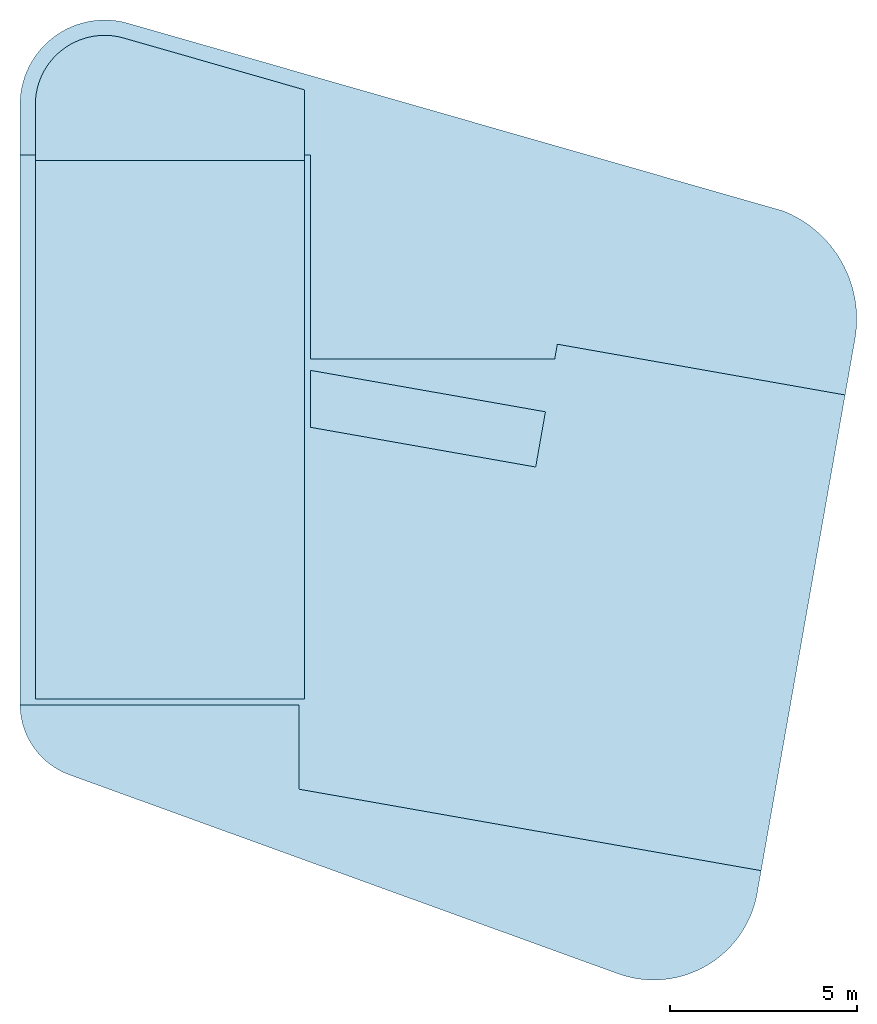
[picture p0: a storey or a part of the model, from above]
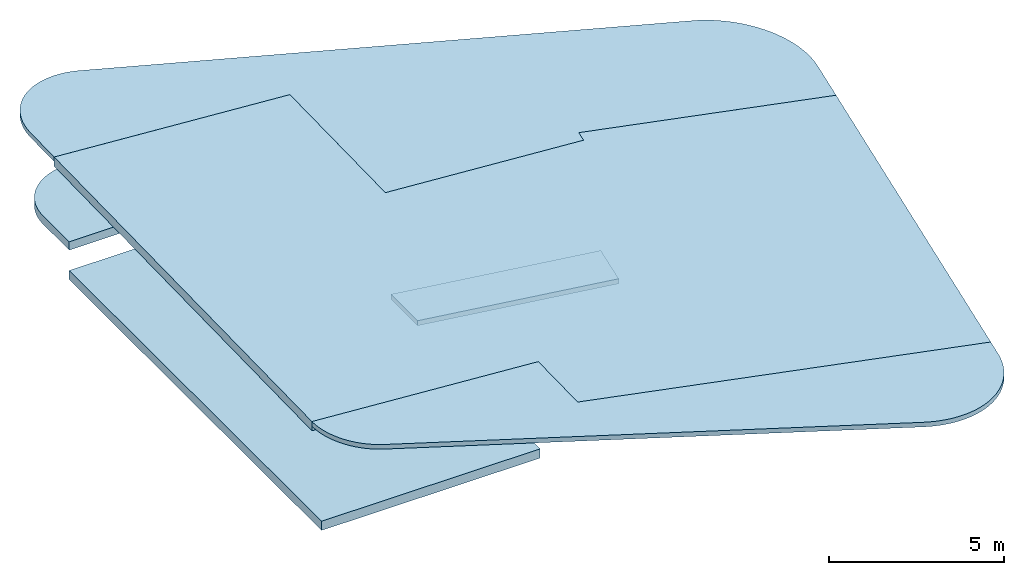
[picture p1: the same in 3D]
Properties of the parts of a building model (IFC2X3)

# File
Description: ViewDefinition [CoordinationView_V2.0, QuantityTakeOffAddOnView]
Time: 2021-04-29T08:18:13
Author: IMd, imd@imdbv.nl
Organization: IMd Raadgevende Ingenieurs
Written by: The EXPRESS Data Manager Version 5.02.0100.07 : 28 Aug 2013
Made in: 20200826_1250(x64) - Exporter 20.2.1.0 - Alternate UI 20.2.1.0
Comment: STEP Physical File produced by: The EXPRESS Data Manager Version 5.02.0100.07 : 28 Aug 2013 * Module: EDMstepFileFactory/EDMstandAlone * Creation date: Thu Apr 29 08:18:13 2021 * Host: mod-prod-vdi-07 * Database: C:\Users\sl\AppData\Local\Temp\82545038-9e77-4e2a-bcb9-289da51b45b7\7ef8d0ce-2a1d-49f6-8344-e9309f1aad8b\ifc * Database version: 5507 * Database creation date: Thu Apr 29 08:18:07 2021 * Schema: IFC2X3 * Model: DataRepository.ifc * Model creation date: Thu Apr 29 08:18:07 2021 * Header model: DataRepository.ifc_HeaderModel * Header model creation date: Thu Apr 29 08:18:07 2021 * EDMuser: sdai-user * EDMgroup: sdai-group * License ID and type: 5605 : Permanent license. Expiry date: * EDMstepFileFactory options: 020000

# IfcProject
Phase: DO

# IfcSite, Default
RefLatitude: 52, 13, 20, 148010; RefLongitude: 5, 11, 12, 352981; RefElevation: 0 mm
Pset_ProductRequirements - Category: Project Information

# IfcBuilding, IFc
LongName: IFc
Pset_BuildingCommon - NumberOfStoreys: 4
Pset_ProductRequirements - Category: Project Information

# IfcBuildingStorey: Level:IMd_hulplevel (3)
In: IFc
Pset_ProductRequirements - Category: Levels
Name | LongName = Pset_AirSideSystemInformation, Name = Pset_ProductRequirements, Name | Elevation (mm)
00 begane grond b.k. ruwe vloer | 00 begane grond b.k. ruwe vloer | -70
01 1e verd. b.k. ruwe vloer | 01 1e verd. b.k. ruwe vloer | 3000
02 2e verd. b.k. ruwe vloer | 02 2e verd. b.k. ruwe vloer | 3700

# IfcBuildingStorey: Level:IMd_niveau naam en peil, -01 kelder
In: IFc
LongName: -01 kelder; Elevation: -4000 mm
Pset_AirSideSystemInformation - Name: Inheiniveau NAP -11,5m
Pset_ProductRequirements - Name: Inheiniveau NAP -11,5m; Category: Levels

# IfcBeam: NLRS_28_SF_LIB_balk buis_generiek_ISR:ø139.7x8 (3)
In: 00 begane grond b.k. ruwe vloer
Type - Pset_BeamCommon - IsExternal: no; LoadBearing: yes; Reference: NLRS_28_SF_LIB_balk buis_generiek_ISR:ø139.7x8
Type - Pset_ProductRequirements - Category: Structural Framing
Type - Pset_QuantityTakeOff - Reference: NLRS_28_SF_LIB_balk buis_generiek_ISR:ø139.7x8
Type - Pset_ReinforcementBarPitchOfBeam - Description: ø139.7x8; Reference: NLRS_28_SF_LIB_balk buis_generiek_ISR:ø139.7x8
Type - S_IMd_IFC_(28)_SF_Stalen liggers - Assembly Code: 28.11; Assembly Description: hoofddraagconstructies; kolommen en liggers, kolom-/liggerconstructies
Classification: 28.11 hoofddraagconstructies; kolommen en liggers, kolom-/liggerconstructies (NL-SfB nummercode); Material: IMd_staal
BaseQuantities - CrossSectionArea: 0.00330954 m2
S_IMd_IFC_(28)_SF_Stalen liggers - Start Extension: 0 mm; Cross-Section Rotation: 0 deg; Family: NLRS_28_SF_LIB_balk buis_generiek_ISR: ø139.7x8; Type: NLRS_28_SF_LIB_balk buis_generiek_ISR: ø139.7x8; Reference Level: Level: 00 begane grond b.k. ruwe vloer; Reference Level Elevation: -70 mm; z Offset Value: 0 mm
Name (NLRS_28_SF_LIB_balk buis_generiek_ISR:ø139.7x8:...) | BaseQuantities, Length (mm) = Cut Length (mm) | OuterSurfaceArea (m2) | GrossVolume (m3) | NetVolume (m3) | Span (mm) = S_IMd_IFC_(28)_SF_Stalen liggers, Length (mm) | Slope (deg) | Start Level Offset (mm) | End Level Offset (mm) | End Extension (mm) | GrossSurfaceArea (m2) | NetSurfaceArea (m2)
1046224 | 5552.17 | 4594393 | 18.3751 | 0.0183834 | 5389.27 | 73.6005 | 678.499 | 5848.51 | 162.901 | 2436738 | 4.60102 | S_IMd_IFC_(28)_SF_Stalen liggers - Comments: (3x)
1046332 | 5520 | 4567775 | 18.2687 | 0.0182769 | 5520 | 78.9309 | 676.053 | 6093.36 | 0 | 2422620 | 4.5744
1046638 | 5481.06 | 4535556 | 18.1398 | 0.0181479 | 5260 | 79 | 702.677 | 5866.04 | 221.064 | 2405532 | 4.54218

# IfcBeam: NLRS_28_SF_LIB_balk hout gelamineerd_generiek_ISR:HB 140x350 (2)
In: 00 begane grond b.k. ruwe vloer
Type - Pset_BeamCommon - IsExternal: no; LoadBearing: yes; Reference: NLRS_28_SF_LIB_balk hout gelamineerd_generiek_ISR:HB 140x350
Type - Pset_ProductRequirements - Category: Structural Framing
Type - Pset_QuantityTakeOff - Reference: NLRS_28_SF_LIB_balk hout gelamineerd_generiek_ISR:HB 140x350
Type - Pset_ReinforcementBarPitchOfBeam - Description: gelamineerde ligger 180x550; Reference: NLRS_28_SF_LIB_balk hout gelamineerd_generiek_ISR:HB 140x350
Type - S_IMd_IFC_(28)_SF_Stalen liggers - Assembly Code: 28.11; Assembly Description: hoofddraagconstructies; kolommen en liggers, kolom-/liggerconstructies
Classification: 28.11 hoofddraagconstructies; kolommen en liggers, kolom-/liggerconstructies (NL-SfB nummercode); Material: IMd_hout
BaseQuantities - GrossSurfaceArea: 0 m2; NetVolume: 0.618238 m3; Length: 12606 mm; NetSurfaceArea: 12.4628 m2
Pset_BeamCommon - Slope: 0 deg; Span: 12606 mm
S_IMd_IFC_(28)_SF_Stalen liggers - Start Level Offset: 0 mm; End Level Offset: 0 mm; Start Extension: 0 mm; End Extension: 0 mm; Cross-Section Rotation: 0 deg; Structural Material: IMd_hout; Family: NLRS_28_SF_LIB_balk hout gelamineerd_generiek_ISR: HB 140x350; Type: NLRS_28_SF_LIB_balk hout gelamineerd_generiek_ISR: HB 140x350; Reference Level: Level: 01 eerste verdieping; Reference Level Elevation: 3000 mm; Elevation at Top: 2982 mm; Elevation at Bottom: 2632 mm; z Offset Value: -18 mm; Length: 12606 mm; Cut Length: 12617.1 mm; Comments: (GL)
Name (NLRS_28_SF_LIB_balk hout gelamineerd_generiek_ISR:HB 140x350:...)
998395
998734

# IfcBeam: NLRS_28_SF_LIB_balk hout gelamineerd_generiek_ISR:HB 180x550 (4)
In: 00 begane grond b.k. ruwe vloer
Type - Pset_BeamCommon - IsExternal: no; LoadBearing: yes; Reference: NLRS_28_SF_LIB_balk hout gelamineerd_generiek_ISR:HB 180x550
Type - Pset_ProductRequirements - Category: Structural Framing
Type - Pset_QuantityTakeOff - Reference: NLRS_28_SF_LIB_balk hout gelamineerd_generiek_ISR:HB 180x550
Type - Pset_ReinforcementBarPitchOfBeam - Description: gelamineerde ligger 180x550; Reference: NLRS_28_SF_LIB_balk hout gelamineerd_generiek_ISR:HB 180x550
Type - S_IMd_IFC_(28)_SF_Stalen liggers - Assembly Code: 28.11; Assembly Description: hoofddraagconstructies; kolommen en liggers, kolom-/liggerconstructies
Classification: 28.11 hoofddraagconstructies; kolommen en liggers, kolom-/liggerconstructies (NL-SfB nummercode); Material: IMd_hout
BaseQuantities - GrossSurfaceArea: 0 m2
Pset_BeamCommon - Slope: 0 deg
S_IMd_IFC_(28)_SF_Stalen liggers - Structural Material: IMd_hout; Family: NLRS_28_SF_LIB_balk hout gelamineerd_generiek_ISR: HB 180x550; Type: NLRS_28_SF_LIB_balk hout gelamineerd_generiek_ISR: HB 180x550; Reference Level: Level: 01 eerste verdieping; Reference Level Elevation: 3000 mm; Start Level Offset: 0 mm; End Level Offset: 0 mm; Start Extension: 0 mm; End Extension: 0 mm; Cross-Section Rotation: 0 deg; Comments: (GL)
Name (NLRS_28_SF_LIB_balk hout gelamineerd_generiek_ISR:HB 180x550:...) | NetVolume (m3) | Span (mm) = S_IMd_IFC_(28)_SF_Stalen liggers, Length (mm) = BaseQuantities, Length (mm) | Elevation at Top (mm) | Elevation at Bottom (mm) | z Offset Value (mm) | Cut Length (mm) | NetSurfaceArea (m2)
996988 | 0.59884 | 6042.16 | 2980 | 2430 | -20 | 6048.89 | 9.02938
997385 | 0.577756 | 5843.05 | 2980 | 2430 | -20 | 5835.92 | 8.71844
997448 | 0.659984 | 6667.73 | 3550 | 3000 | 550 | 6666.51 | 9.9311
997450 | 0.637379 | 6435.15 | 3550 | 3000 | 550 | 6438.17 | 9.59773

# IfcBeam: NLRS_28_SF_LIB_balk hout gelamineerd_generiek_ISR:HB 271x550 (2)
In: 00 begane grond b.k. ruwe vloer
Type - Pset_BeamCommon - IsExternal: no; LoadBearing: yes; Reference: NLRS_28_SF_LIB_balk hout gelamineerd_generiek_ISR:HB 271x550
Type - Pset_ProductRequirements - Category: Structural Framing
Type - Pset_QuantityTakeOff - Reference: NLRS_28_SF_LIB_balk hout gelamineerd_generiek_ISR:HB 271x550
Type - Pset_ReinforcementBarPitchOfBeam - Description: gelamineerde ligger 180x550; Reference: NLRS_28_SF_LIB_balk hout gelamineerd_generiek_ISR:HB 271x550
Type - S_IMd_IFC_(28)_SF_Stalen liggers - Assembly Code: 28.11; Assembly Description: hoofddraagconstructies; kolommen en liggers, kolom-/liggerconstructies
Classification: 28.11 hoofddraagconstructies; kolommen en liggers, kolom-/liggerconstructies (NL-SfB nummercode); Material: IMd_hout
BaseQuantities - GrossSurfaceArea: 0 m2
Pset_BeamCommon - Slope: 0 deg
S_IMd_IFC_(28)_SF_Stalen liggers - Start Level Offset: 0 mm; End Level Offset: 0 mm; Cross-Section Rotation: 0 deg; Structural Material: IMd_hout; Family: NLRS_28_SF_LIB_balk hout gelamineerd_generiek_ISR: HB 271x550; Type: NLRS_28_SF_LIB_balk hout gelamineerd_generiek_ISR: HB 271x550; Reference Level: Level: 01 eerste verdieping; Reference Level Elevation: 3000 mm; Elevation at Top: 2982 mm; Elevation at Bottom: 2432 mm; z Offset Value: -18 mm; Comments: (GL)
Name (NLRS_28_SF_LIB_balk hout gelamineerd_generiek_ISR:HB 271x550:...) | NetVolume (m3) | Span (mm) = S_IMd_IFC_(28)_SF_Stalen liggers, Length (mm) = BaseQuantities, Length (mm) | Cut Length (mm) | Start Extension (mm) | End Extension (mm) | NetSurfaceArea (m2)
1018371 | 1.50049 | 10560 | 10067 | -475.07 | -17.9296 | 16.8281
1018509 | 0.87075 | 7600 | 5842 | -1761.23 | 3.23142 | 9.89066

# IfcBuildingElementProxy: 90_Site_Nulpunt kubus IMd (terrein):90_Kubus 1x1x1m, 90_Site_Nulpunt kubus IMd (terrein):90_Kubus 1x1x1m:699363
In: 00 begane grond b.k. ruwe vloer
Type - Classification: 0- INDIRECTE PROJECTVOORZIENINGEN (NL-SfB nummercode); Material: IMd_(cb)_constructief
Type - Pset_BuildingElementProxyCommon - Reference: 90_Site_Nulpunt kubus IMd (terrein):90_Kubus 1x1x1m
Type - Pset_ProductRequirements - Category: Site
Type - Pset_QuantityTakeOff - Reference: 90_Site_Nulpunt kubus IMd (terrein):90_Kubus 1x1x1m
Pset_BuildingElementProxyCommon - sets with these values: 2
Pset_ProvisionForVoid - Width: 2000 mm; Height: 750 mm; Depth: 2000 mm

# IfcBuildingElementProxy: Bestaande kelder:Bestaande kelder, Bestaande kelder:Bestaande kelder:998988
In: -01 kelder
Type - Material: IMd_beton_IHWG
Type - Pset_BuildingElementProxyCommon - Reference: Bestaande kelder:Bestaande kelder
Type - Pset_ProductRequirements - Category: Generic Models
Type - Pset_QuantityTakeOff - Reference: Bestaande kelder:Bestaande kelder
Pset_BuildingElementProxyCommon - sets with these values: 2
Pset_ProvisionForVoid - Width: 3850 mm; Depth: 3850 mm

# IfcColumn: NLRS_28_SC_TLB_kolom buis_generiek_ISR:ø88.9x5 (20)
In: 01 1e verd. b.k. ruwe vloer
Type - PredefinedType: COLUMN; Classification: 28.10 hoofddraagconstructies; kolommen en liggers, algemeen (verzamelniveau) (NL-SfB nummercode); Material: <Unnamed>, IMd_staal
Type - Pset_ColumnCommon - IsExternal: no; LoadBearing: yes; Reference: NLRS_28_SC_TLB_kolom buis_generiek_ISR:ø88.9x5
Type - Pset_ProductRequirements - Category: Structural Columns
Type - Pset_QuantityTakeOff - Reference: NLRS_28_SC_TLB_kolom buis_generiek_ISR:ø88.9x5
Type - Pset_ReinforcementBarPitchOfColumn - Description: Stalen kolom ø88.9x5; Reference: NLRS_28_SC_TLB_kolom buis_generiek_ISR:ø88.9x5
Type - S_IMd_IFC_(28)_SCO_Kolommen - Assembly Code: 28.10; Assembly Description: hoofddraagconstructies; kolommen en liggers, algemeen (verzamelniveau)
Material: IMd_staal
BaseQuantities - GrossSurfaceArea: 0 m2
S_IMd_IFC_(28)_SCO_Kolommen - Family: NLRS_28_SC_TLB_kolom buis_generiek_ISR: ø88.9x5; Type: NLRS_28_SC_TLB_kolom buis_generiek_ISR: ø88.9x5; Base Level: Level: 02 tweede verdieping; Top Level: Level: 03 derde verdieping
Name (NLRS_28_SC_TLB_kolom buis_generiek_ISR:ø88.9x5:...) | NetVolume (m3) = Volume (m3) | Base Offset (mm) | Top Offset (mm) | Column Location Mark | Length (mm)
1047423 | 0.00336048 | 1350 | 1600 | A-4(256.37) | 2550
1047770 | 0.00336048 | 1350 | 1600 | A(333.378)-5(125.312) | 2550
1047787 | 0.00316281 | 1350 | 1450 | A(2097.437)-6 | 2400
1047846 | 0.00382172 | -200 | 400 | C(839.059)-6 | 2900
1047913 | 0.00368994 | -200 | 300 | D(-1214.646)-6 | 2800
1047932 | 0.00355816 | -200 | 200 | D(377.211)-6 | 2700
1047951 | 0.00342637 | -200 | 100 | E(-1602.817)-6(-90.142) | 2600
1047968 | 0.0032287 | -200 | -50 | E-3(284.878) | 2450
1047989 | 0.00316281 | -200 | -100 | E-12(281.934) | 2400
1048010 | 0.00421707 | -200 | 700 | B-7 | 3200
1048031 | 0.00434886 | -200 | 800 | B(-1493.08)-7 | 3300
1048050 | 0.00454653 | -200 | 950 | B(-3034.21)-7 | 3450
1048069 | 0.00467832 | -200 | 1050 | A(2643.434)-7 | 3550
1048092 | 0.0048101 | -200 | 1150 | A(1119.43)-7 | 3650
1048111 | 0.00500778 | -200 | 1300 | A(47.724)-1(-487.082) | 3800
1049851 | 0.00303102 | 1350 | 1350 | 5(503.127)-6 | 2300
1049870 | 0.00289924 | 1350 | 1250 | 5(62.107)-6 | 2200
1049889 | 0.00270156 | 1350 | 1100 | B(-464.475)-6 | 2050
1049908 | 0.00256978 | 1350 | 1000 | B(1073.543)-6 | 1950
1049927 | 0.002438 | 1350 | 900 | B(2660.593)-6 | 1850

# IfcColumn: NLRS_28_SC_TLB_kolom vierkant hout_generiek_ISR:180x180 (GL) (3)
In: 00 begane grond b.k. ruwe vloer
Type - PredefinedType: COLUMN; Classification: 28.10 hoofddraagconstructies; kolommen en liggers, algemeen (verzamelniveau) (NL-SfB nummercode); Material: <Unnamed>, ISR_Hout
Type - Pset_ColumnCommon - IsExternal: no; LoadBearing: yes; Reference: NLRS_28_SC_TLB_kolom vierkant hout_generiek_ISR:180x180 (GL)
Type - Pset_ProductRequirements - Category: Structural Columns
Type - Pset_QuantityTakeOff - Reference: NLRS_28_SC_TLB_kolom vierkant hout_generiek_ISR:180x180 (GL)
Type - Pset_ReinforcementBarPitchOfColumn - Description: houten kolom 180x10mm; Reference: NLRS_28_SC_TLB_kolom vierkant hout_generiek_ISR:180x180 (GL)
Type - S_IMd_IFC_(28)_SCO_Kolommen - Assembly Code: 28.10; Assembly Description: hoofddraagconstructies; kolommen en liggers, algemeen (verzamelniveau)
Material: ISR_Hout
BaseQuantities - CrossSectionArea: 0.97992 m2; NetVolume: 0.0852768 m3
S_IMd_IFC_(28)_SCO_Kolommen - Base Offset: 0 mm; Family: NLRS_28_SC_TLB_kolom vierkant hout_generiek_ISR: 180x180 (GL); Type: NLRS_28_SC_TLB_kolom vierkant hout_generiek_ISR: 180x180 (GL); Base Level: Level: 00 begane grond; Top Level: Level: 01 1e verd. o.k. ruwe vloer; Top Offset: -48 mm; Length: 2632 mm; Volume: 0.0852768 m3
Name (NLRS_28_SC_TLB_kolom vierkant hout_generiek_ISR:180x180 (GL):...) | Column Location Mark
1003820 | D-9
1004880 | D-10
1004895 | D-11

# IfcOpeningElement: Opening (24)
Pset_OpeningElementCommon - sets with these values: 2
Name | In | Classification | Roughness (mm) | Reference | Category | Height (mm) | BaseQuantities, Width (mm)
Basic Wall:NLRS_28_WA HSB_d=271:983221 | 00 begane grond b.k. ruwe vloer | 28.20 hoofddraagconstructies; wanden en vloeren, algemeen (verzamelniveau) (NL-SfB nummercode) | 304.8 | Basic Wall:Model Lines | <Sketch> | BaseQuantities - Area: 18.2992 m2
Basic Wall:NLRS_28_WA HSB_d=271:983221 | 00 begane grond b.k. ruwe vloer | 28.20 hoofddraagconstructies; wanden en vloeren, algemeen (verzamelniveau) (NL-SfB nummercode) | 304.8 | Basic Wall:Model Lines | <Sketch> | 2400 | 1567
Basic Wall:NLRS_28_WA HSB_d=271:983221 | 00 begane grond b.k. ruwe vloer | 28.20 hoofddraagconstructies; wanden en vloeren, algemeen (verzamelniveau) (NL-SfB nummercode) | 304.8 | Basic Wall:Model Lines | <Sketch> | 2400 | 1064
Basic Wall:NLRS_28_WA HSB_d=271:983221 | 00 begane grond b.k. ruwe vloer | 28.20 hoofddraagconstructies; wanden en vloeren, algemeen (verzamelniveau) (NL-SfB nummercode) | 304.8 | Basic Wall:Model Lines | <Sketch> | 2070 | 1280
2 x Basic Wall:NLRS_28_WA HSB_d=271:983221 | 00 begane grond b.k. ruwe vloer | 28.20 hoofddraagconstructies; wanden en vloeren, algemeen (verzamelniveau) (NL-SfB nummercode) | 304.8 | Basic Wall:Model Lines | <Sketch> | 2470 | 2467
Basic Wall:NLRS_28_WA HSB_d=271:983221 | 00 begane grond b.k. ruwe vloer | 28.20 hoofddraagconstructies; wanden en vloeren, algemeen (verzamelniveau) (NL-SfB nummercode) | 304.8 | Basic Wall:Model Lines | <Sketch> | 2470 | 1667
Basic Wall:NLRS_28_WA HSB_d=271:983221 | 00 begane grond b.k. ruwe vloer | 28.20 hoofddraagconstructies; wanden en vloeren, algemeen (verzamelniveau) (NL-SfB nummercode) | 304.8 | Basic Wall:Model Lines | <Sketch> | 7190 | 1400.98
Basic Wall:NLRS_28_WA HSB_d=271:983221 | 00 begane grond b.k. ruwe vloer | 28.20 hoofddraagconstructies; wanden en vloeren, algemeen (verzamelniveau) (NL-SfB nummercode) | 304.8 | Basic Wall:Model Lines | <Sketch> | 2070 | 1199.27
Basic Wall:NLRS_28_WA HSB_d=271:983221 | 00 begane grond b.k. ruwe vloer | 28.20 hoofddraagconstructies; wanden en vloeren, algemeen (verzamelniveau) (NL-SfB nummercode) | 304.8 | Basic Wall:Model Lines | <Sketch> | BaseQuantities - Area: 7.4797 m2
Basic Wall:NLRS_28_WA HSB_d=271:983221 | 00 begane grond b.k. ruwe vloer | 28.20 hoofddraagconstructies; wanden en vloeren, algemeen (verzamelniveau) (NL-SfB nummercode) | 304.8 | Basic Wall:Model Lines | <Sketch> | BaseQuantities - Area: 13.1017 m2
Basic Wall:NLRS_28_WA HSB_d=271:983221 | 00 begane grond b.k. ruwe vloer | 28.20 hoofddraagconstructies; wanden en vloeren, algemeen (verzamelniveau) (NL-SfB nummercode) | 304.8 | Basic Wall:Model Lines | <Sketch> | 5630 | 1285.92
Basic Wall:NLRS_28_WA HSB_d=271:983221 | 00 begane grond b.k. ruwe vloer | 28.20 hoofddraagconstructies; wanden en vloeren, algemeen (verzamelniveau) (NL-SfB nummercode) | 304.8 | Basic Wall:Model Lines | <Sketch> | 2470 | 1084
Basic Wall:NLRS_28_WA HSB_d=271:983221 | 00 begane grond b.k. ruwe vloer | 28.20 hoofddraagconstructies; wanden en vloeren, algemeen (verzamelniveau) (NL-SfB nummercode) | 304.8 | Basic Wall:Model Lines | <Sketch> | 2457 | 1084
Basic Wall:NLRS_28_WA HSB_d=271:983221 | 00 begane grond b.k. ruwe vloer | 28.20 hoofddraagconstructies; wanden en vloeren, algemeen (verzamelniveau) (NL-SfB nummercode) | 304.8 | Basic Wall:Model Lines | <Sketch> | BaseQuantities - Area: 6.97703 m2
Basic Wall:NLRS_28_WA HSB_d=271:983221 | 00 begane grond b.k. ruwe vloer | 28.20 hoofddraagconstructies; wanden en vloeren, algemeen (verzamelniveau) (NL-SfB nummercode) | 304.8 | Basic Wall:Model Lines | <Sketch> | 7620 | 4084
Basic Wall:NLRS_28_WA HSB_d=271:983221 | 00 begane grond b.k. ruwe vloer | 28.20 hoofddraagconstructies; wanden en vloeren, algemeen (verzamelniveau) (NL-SfB nummercode) | 304.8 | Basic Wall:Model Lines | <Sketch> | BaseQuantities - Area: 2.688 m2
Basic Wall:NLRS_28_WA HSB_d=271:983221 | 00 begane grond b.k. ruwe vloer | 28.20 hoofddraagconstructies; wanden en vloeren, algemeen (verzamelniveau) (NL-SfB nummercode) | 304.8 | Basic Wall:Model Lines | <Sketch> | 863 | 1400
Basic Wall:NLRS_28_WA HSB_d=271:983221 | 00 begane grond b.k. ruwe vloer | 28.20 hoofddraagconstructies; wanden en vloeren, algemeen (verzamelniveau) (NL-SfB nummercode) | 304.8 | Basic Wall:Model Lines | <Sketch> | BaseQuantities - Area: 10.4605 m2
Basic Wall:NLRS_28_WA HSB_d=271:983221 | 00 begane grond b.k. ruwe vloer | 28.20 hoofddraagconstructies; wanden en vloeren, algemeen (verzamelniveau) (NL-SfB nummercode) | 304.8 | Basic Wall:Model Lines | <Sketch> | 7190 | 1642.47
Basic Wall:NLRS_16_WA Funderingsbalk_beton_ihwg_500x600:1000701:1 | -01 kelder | 16.10 funderingsconstructies; voeten en balken, algemeen (verzamelniveau) (NL-SfB nummercode) | 304.8 | Basic Wall:NLRS_16_WA Funderingsbalk_beton_ihwg_500x600 | Walls | S_IMd_IFC_(--)_WA_Wanden - Assembly Code: 16.10; Assembly Description: funderingsconstructies; voeten en balken, algemeen (verzamelniveau); Description: Balk 500x600; Family: Basic Wall: NLRS_16_WA Funderingsbalk_beton_ihwg_500x600; Type: Basic Wall: NLRS_16_WA Funderingsbalk_beton_ihwg_500x600; Structural Material: IMd_beton_IHWG; Base Constraint: Level: 00 o.k. fundering; Base Offset: -140 mm; Top Constraint: Level: 00 b.k. fundering; Top Offset: -140 mm; Unconnected Height: 600 mm; Length: 9784.67 mm; Width: 500 mm; Area: 5.2708 m2; Volume: 2.6354 m3; Comments: Betonwand D= mm; IfcExportAs: IFcBeam
Floor:NLRS_23_FL Beton_ihwg_d=80:1001667:2 | 00 begane grond b.k. ruwe vloer | 23.20 vloeren; constructief, algemeen (verzamelniveau) (NL-SfB nummercode) | 304.8 | Floor:NLRS_23_FL Beton_ihwg_d=80 | Floors | BaseQuantities - Area: 2.4328 m2; Depth: 80 mm; S_IMd_IFC_(--)_FL_Vloeren - Assembly Code: 23.20; Assembly Description: vloeren; constructief, algemeen (verzamelniveau); Structural Material: IMd_beton_IHWG; Family: Floor: NLRS_23_FL Beton_ihwg_d=80; Type: Floor: NLRS_23_FL Beton_ihwg_d=80; Type Comments: 80; Level: Level: 00 begane grond b.k. ruwe vloer; Height Offset From Level: 60 mm; Elevation at Top: -10 mm; Elevation at Bottom: -90 mm; Area: 228.099 m2; Volume: 18.2479 m3; Perimeter: 66236.6 mm; Keynote: 21,51
Basic Wall:NLRS_16_WA Funderingsbalk_beton_prefab_300x800:1015176 | 00 begane grond b.k. ruwe vloer | 16.10 funderingsconstructies; voeten en balken, algemeen (verzamelniveau) (NL-SfB nummercode) |  | 00_GM_IMd-Void bk schuin:00_GM_IMd-Void bk schuin | Generic Models | 160 | 1000 | BaseQuantities - Depth: 454.558 mm
Basic Wall:NLRS_16_WA Funderingsbalk_beton_prefab_300x800:1015811 | 00 begane grond b.k. ruwe vloer | 16.10 funderingsconstructies; voeten en balken, algemeen (verzamelniveau) (NL-SfB nummercode) |  | 00_GM_IMd-Void bk schuin:00_GM_IMd-Void bk schuin | Generic Models | 140 | 1000 | BaseQuantities - Depth: 590 mm

# IfcOpeningElement: Recess (2)
In: -01 kelder
Classification: 16.10 funderingsconstructies; voeten en balken, algemeen (verzamelniveau) (NL-SfB nummercode)
BaseQuantities - Height: 700 mm; Width: 140 mm
Pset_OpeningElementCommon - Reference: 00_GM_IMd-Void bk schuin:00_GM_IMd-Void bk schuin; sets with these values: 2
Pset_ProductRequirements - Category: Generic Models
Name (Basic Wall:NLRS_16_WA Funderingsbalk_beton_ihwg_500x600:...) | Depth (mm)
1015409 | 397.948
1015409 | 318.048

# IfcPile: NLRS_17_SFO_TLB_funderingspaal rond_gen_ISR:Type 01_ø380/450_Fd=900kN (22)
In: 00 begane grond b.k. ruwe vloer
Classification: 17 paalfunderingen (NL-SfB nummercode); Material: IMd_beton_IHWG
Pset_ProductRequirements - Category: Structural Foundations
Pset_QuantityTakeOff - Reference: NLRS_17_SFO_TLB_funderingspaal rond_gen_ISR:Type 01_ø380/450_Fd=900kN
S_IMd_IFC_(17)_SFO_Palen - Assembly Code: 17; Assembly Description: paalfunderingen; Family: NLRS_17_SFO_TLB_funderingspaal rond_gen_ISR: Type 01_ø380/450_Fd=900kN; Type: NLRS_17_SFO_TLB_funderingspaal rond_gen_ISR: Type 01_ø380/450_Fd=900kN; Structural Material: IMd_beton_IHWG; Level: Level: 00 begane grond; Elevation at Top: -1110 mm; Elevation at Bottom: -13000 mm; Afhakhoogte-Code: a; bruto_paal_lengte: 11890 mm; netto_paal_lengte: 11890 mm; verticaal_netto_lengte: 11890 mm; Volume: 1.34842 m3; voet_diameter: 450 mm; draagvermogen_druk: 900 kN; draagvermogen_trek: 0 kN; IfcExportAs: IfcPile
Name (NLRS_17_SFO_TLB_funderingspaal rond_gen_ISR:Type 01_ø380/450_Fd=900kN:...)
1033195
1033640
1033655
1033666
1033677
1033686
1033697
1033716
1033727
1033765
1033776
1033817
1033826
1033877
1033923
1033938
1034017
1034019
1034030
1034032
1034043
1034045

# IfcSlab: Floor:NLRS_23_FL Beton_ihwg_d=170, Floor:NLRS_23_FL Beton_ihwg_d=170:1010961
In: 00 begane grond b.k. ruwe vloer
Type - PredefinedType: FLOOR; Material: IMd_beton_IHWG 170 mm
Type - Pset_ElementShading - Roughness: 304.8 mm
Type - Pset_ProductRequirements - Category: Floors
Type - Pset_QuantityTakeOff - Reference: Floor:NLRS_23_FL Beton_ihwg_d=170
Type - Pset_ReinforcementBarPitchOfSlab - Description: IHWG170; Reference: Floor:NLRS_23_FL Beton_ihwg_d=170
Type - Pset_SlabCommon - IsExternal: no; Reference: Floor:NLRS_23_FL Beton_ihwg_d=170
Type - S_IMd_IFC_(--)_FL_Vloeren - Assembly Code: 23.20; Assembly Description: vloeren; constructief, algemeen (verzamelniveau); Structural Material: IMd_beton_IHWG; Type Comments: 170; Keynote: 21,51
Classification: 23.20 vloeren; constructief, algemeen (verzamelniveau) (NL-SfB nummercode)
Pset_SlabCommon - LoadBearing: yes; PitchAngle: 0 deg
S_IMd_IFC_(--)_FL_Vloeren - Family: Floor: NLRS_23_FL Beton_ihwg_d=170; Type: Floor: NLRS_23_FL Beton_ihwg_d=170; Level: Level: 00 begane grond b.k. ruwe vloer; Height Offset From Level: -300 mm; Elevation at Top: -370 mm; Elevation at Bottom: -540 mm; Area: 6.39231 m2; Volume: 1.08664 m3; Perimeter: 45500.2 mm
BaseQuantities - NetArea: 20.5196 m2; NetVolume: 1.08664 m3; Perimeter: 45500.2 mm

# IfcSlab: Floor:NLRS_23_FL Beton_ihwg_d=300, Floor:NLRS_23_FL Beton_ihwg_d=300:1010647
In: 00 begane grond b.k. ruwe vloer
Type - PredefinedType: FLOOR; Material: IMd_beton_IHWG 300 mm
Type - Pset_ElementShading - Roughness: 304.8 mm
Type - Pset_ProductRequirements - Category: Floors
Type - Pset_QuantityTakeOff - Reference: Floor:NLRS_23_FL Beton_ihwg_d=300
Type - Pset_ReinforcementBarPitchOfSlab - Description: IHWG300; Reference: Floor:NLRS_23_FL Beton_ihwg_d=300
Type - Pset_SlabCommon - IsExternal: no; Reference: Floor:NLRS_23_FL Beton_ihwg_d=300
Type - S_IMd_IFC_(--)_FL_Vloeren - Assembly Code: 23.20; Assembly Description: vloeren; constructief, algemeen (verzamelniveau); Structural Material: IMd_beton_IHWG; Type Comments: 300; Keynote: 21,51
Classification: 23.20 vloeren; constructief, algemeen (verzamelniveau) (NL-SfB nummercode)
Pset_SlabCommon - LoadBearing: yes; PitchAngle: 0 deg
S_IMd_IFC_(--)_FL_Vloeren - Height Offset From Level: 0 mm; Family: Floor: NLRS_23_FL Beton_ihwg_d=300; Type: Floor: NLRS_23_FL Beton_ihwg_d=300; Level: Level: 00 begane grond b.k. ruwe vloer; Elevation at Top: -70 mm; Elevation at Bottom: -370 mm; Area: 24.2966 m2; Volume: 7.28899 m3; Perimeter: 23764.5 mm
BaseQuantities - GrossArea: 24.2964 m2; NetArea: 55.7226 m2; GrossVolume: 7288.92 m3; NetVolume: 7.28899 m3; Perimeter: 23764.5 mm; Width: 300 mm

# IfcSlab: Floor:NLRS_23_FL Beton_ihwg_d=80, Floor:NLRS_23_FL Beton_ihwg_d=80:1001667
In: 00 begane grond b.k. ruwe vloer
Type - PredefinedType: FLOOR; Material: IMd_beton_IHWG 80 mm
Type - Pset_ElementShading - Roughness: 304.8 mm
Type - Pset_ProductRequirements - Category: Floors
Type - Pset_QuantityTakeOff - Reference: Floor:NLRS_23_FL Beton_ihwg_d=80
Type - Pset_ReinforcementBarPitchOfSlab - Description: IHWG80; Reference: Floor:NLRS_23_FL Beton_ihwg_d=80
Type - Pset_SlabCommon - IsExternal: no; Reference: Floor:NLRS_23_FL Beton_ihwg_d=80
Type - S_IMd_IFC_(--)_FL_Vloeren - Assembly Code: 23.20; Assembly Description: vloeren; constructief, algemeen (verzamelniveau); Structural Material: IMd_beton_IHWG; Type Comments: 80; Keynote: 21,51
Classification: 23.20 vloeren; constructief, algemeen (verzamelniveau) (NL-SfB nummercode)
Pset_SlabCommon - LoadBearing: yes; PitchAngle: 0 deg
S_IMd_IFC_(--)_FL_Vloeren - Family: Floor: NLRS_23_FL Beton_ihwg_d=80; Type: Floor: NLRS_23_FL Beton_ihwg_d=80; Level: Level: 00 begane grond b.k. ruwe vloer; Height Offset From Level: 60 mm; Elevation at Top: -10 mm; Elevation at Bottom: -90 mm; Area: 228.099 m2; Volume: 18.2479 m3; Perimeter: 66236.6 mm
BaseQuantities - GrossArea: 230.531 m2; NetArea: 461.497 m2; NetVolume: 18.2479 m3; Perimeter: 66236.6 mm

# IfcSlab: Floor:NLRS_23_FL Houten kanaalplaat_d=320 (2)
In: 02 2e verd. b.k. ruwe vloer
Type - PredefinedType: FLOOR; Material: IMd_hout 320 mm
Type - Pset_ElementShading - Roughness: 304.8 mm
Type - Pset_ProductRequirements - Category: Floors
Type - Pset_QuantityTakeOff - Reference: Floor:NLRS_23_FL Houten kanaalplaat_d=320
Type - Pset_ReinforcementBarPitchOfSlab - Description: houten KP320; Reference: Floor:NLRS_23_FL Houten kanaalplaat_d=320
Type - Pset_SlabCommon - Reference: Floor:NLRS_23_FL Houten kanaalplaat_d=320; IsExternal: no
Type - S_IMd_IFC_(--)_FL_Vloeren - Assembly Code: 23.21; Assembly Description: vloeren; constructief, vrijdragende vloeren; Structural Material: IMd_hout; Keynote: 23,42
Classification: 23.21 vloeren; constructief, vrijdragende vloeren (NL-SfB nummercode)
Pset_SlabCommon - LoadBearing: yes
S_IMd_IFC_(--)_FL_Vloeren - Family: Floor: NLRS_23_FL Houten kanaalplaat_d=320; Type: Floor: NLRS_23_FL Houten kanaalplaat_d=320; Height Offset From Level: 0 mm
Name (Floor:NLRS_23_FL Houten kanaalplaat_d=320:...) | PitchAngle (deg) | Level | Area (m2) = GrossArea (m2) | Volume (m3) = NetVolume (m3) | S_IMd_IFC_(--)_FL_Vloeren, Perimeter (mm) = BaseQuantities, Perimeter (mm) | NetArea (m2) | GrossVolume (m3) | Width (mm)
978757 | 0 | Level: 02 2e verd. b.k. ruwe vloer | 103.68 | 33.1776 | 43200 | 221.184 | 33177.6 | 320 | S_IMd_IFC_(--)_FL_Vloeren - Elevation at Top: 3700 mm; Elevation at Bottom: 3380 mm
980562 | 4.18085 | Level: 03 derde verdieping | 281.9 | 90.208 | 77819.3 | 588.768 | 90448.7 | 320.854

# IfcSlab: Floor:NLRS_23_FL Houten_balklaag_59x156+underlayment_d=18 (2)
Type - PredefinedType: FLOOR; Material: IMd_underlayment 18 mm, IMd_hout 156 mm
Type - Pset_ElementShading - Roughness: 304.8 mm
Type - Pset_ProductRequirements - Category: Floors
Type - Pset_QuantityTakeOff - Reference: Floor:NLRS_23_FL Houten_balklaag_59x156+underlayment_d=18
Type - Pset_ReinforcementBarPitchOfSlab - Description: HB59x156; Reference: Floor:NLRS_23_FL Houten_balklaag_59x156+underlayment_d=18
Type - Pset_SlabCommon - IsExternal: no; Reference: Floor:NLRS_23_FL Houten_balklaag_59x156+underlayment_d=18
Type - S_IMd_IFC_(--)_FL_Vloeren - Assembly Code: 23.20; Assembly Description: vloeren; constructief, algemeen (verzamelniveau); Structural Material: IMd_underlayment; Type Comments: h.o.h. 400mm; Keynote: 24,52
Classification: 23.20 vloeren; constructief, algemeen (verzamelniveau) (NL-SfB nummercode)
Pset_SlabCommon - LoadBearing: yes; PitchAngle: 0 deg
S_IMd_IFC_(--)_FL_Vloeren - Family: Floor: NLRS_23_FL Houten_balklaag_59x156+underlayment_d=18; Type: Floor: NLRS_23_FL Houten_balklaag_59x156+underlayment_d=18
BaseQuantities - Width: 174 mm
Name (Floor:NLRS_23_FL Houten_balklaag_59x156+underlayment_d=18:...) | In | Height Offset From Level (mm) | Level | Elevation at Top (mm) | Elevation at Bottom (mm) | Area (m2) = GrossArea (m2) | Volume (m3) = NetVolume (m3) | S_IMd_IFC_(--)_FL_Vloeren, Perimeter (mm) = BaseQuantities, Perimeter (mm) | NetArea (m2) | GrossVolume (m3)
1040864 | 02 2e verd. b.k. ruwe vloer | 0 | Level: 02 2e verd. b.k. ruwe vloer | 3700 | 3526 | 9.35868 | 1.62841 | 15507.4 | 21.4157 | 1628.41
1041221 | 01 1e verd. b.k. ruwe vloer | -702 | Level: 02 tweede verdieping | 2998 | 2824 | 7.37644 | 1.2835 | 13907.1 | 17.1727 | 1283.5

# IfcSlab: Floor:NLRS_23_FL Houten_balklaag_71x246+underlayment_d=18 (2)
In: 00 begane grond b.k. ruwe vloer
Type - PredefinedType: FLOOR; Material: IMd_underlayment 18 mm, IMd_hout 246 mm
Type - Pset_ElementShading - Roughness: 304.8 mm
Type - Pset_ProductRequirements - Category: Floors
Type - Pset_QuantityTakeOff - Reference: Floor:NLRS_23_FL Houten_balklaag_71x246+underlayment_d=18
Type - Pset_ReinforcementBarPitchOfSlab - Description: HB71x246; Reference: Floor:NLRS_23_FL Houten_balklaag_71x246+underlayment_d=18
Type - Pset_SlabCommon - IsExternal: no; Reference: Floor:NLRS_23_FL Houten_balklaag_71x246+underlayment_d=18
Type - S_IMd_IFC_(--)_FL_Vloeren - Assembly Code: 23.20; Assembly Description: vloeren; constructief, algemeen (verzamelniveau); Structural Material: IMd_underlayment; Type Comments: h.o.h. 400mm; Keynote: 24,52
Classification: 23.20 vloeren; constructief, algemeen (verzamelniveau) (NL-SfB nummercode)
Pset_SlabCommon - LoadBearing: yes; PitchAngle: 0 deg
S_IMd_IFC_(--)_FL_Vloeren - Height Offset From Level: 0 mm; Family: Floor: NLRS_23_FL Houten_balklaag_71x246+underlayment_d=18; Type: Floor: NLRS_23_FL Houten_balklaag_71x246+underlayment_d=18; Level: Level: 01 eerste verdieping; Elevation at Top: 3000 mm; Elevation at Bottom: 2736 mm
BaseQuantities - Width: 264 mm
Name (Floor:NLRS_23_FL Houten_balklaag_71x246+underlayment_d=18:...) | Area (m2) | Volume (m3) = NetVolume (m3) | S_IMd_IFC_(--)_FL_Vloeren, Perimeter (mm) = BaseQuantities, Perimeter (mm) | GrossArea (m2) | NetArea (m2) | GrossVolume (m3)
978866 | 90.72 | 23.9501 | 39600 | 90.72 | 191.894 | 23950.1
979456 | 18.2354 | 4.81417 | 19708 | 18.2355 | 41.6737 | 4814.17

# IfcSlab: Floor:NLRS_23_FL Houten_balklaag_71x271+underlayment_d=18 (2)
Type - PredefinedType: FLOOR; Material: IMd_underlayment 18 mm, IMd_hout 271 mm
Type - Pset_ElementShading - Roughness: 304.8 mm
Type - Pset_ProductRequirements - Category: Floors
Type - Pset_QuantityTakeOff - Reference: Floor:NLRS_23_FL Houten_balklaag_71x271+underlayment_d=18
Type - Pset_ReinforcementBarPitchOfSlab - Description: HB71x271; Reference: Floor:NLRS_23_FL Houten_balklaag_71x271+underlayment_d=18
Type - Pset_SlabCommon - IsExternal: no; Reference: Floor:NLRS_23_FL Houten_balklaag_71x271+underlayment_d=18
Type - S_IMd_IFC_(--)_FL_Vloeren - Assembly Code: 23.20; Assembly Description: vloeren; constructief, algemeen (verzamelniveau); Structural Material: IMd_underlayment; Type Comments: h.o.h. 400mm; Keynote: 24,52
Classification: 23.20 vloeren; constructief, algemeen (verzamelniveau) (NL-SfB nummercode)
Pset_SlabCommon - LoadBearing: yes; PitchAngle: 0 deg
S_IMd_IFC_(--)_FL_Vloeren - Family: Floor: NLRS_23_FL Houten_balklaag_71x271+underlayment_d=18; Type: Floor: NLRS_23_FL Houten_balklaag_71x271+underlayment_d=18
BaseQuantities - Width: 289 mm
Name (Floor:NLRS_23_FL Houten_balklaag_71x271+underlayment_d=18:...) | In | Level | Height Offset From Level (mm) | Elevation at Top (mm) | Elevation at Bottom (mm) | Area (m2) | Volume (m3) = NetVolume (m3) | S_IMd_IFC_(--)_FL_Vloeren, Perimeter (mm) = BaseQuantities, Perimeter (mm) | GrossArea (m2) | NetArea (m2) | GrossVolume (m3)
979812 | 02 2e verd. b.k. ruwe vloer | Level: 02 2e verd. b.k. ruwe vloer | 1000 | 4700 | 4411 | 19.6394 | 5.67565 | 19039 | 19.6392 | 44.7811 | 5675.74
980166 | 01 1e verd. b.k. ruwe vloer | Level: 01 1e verd. b.k. ruwe vloer | 0 | 3000 | 2711 | 26.7737 | 7.73752 | 20657.3 | 26.7739 | 59.5174 | 7737.66

# IfcSlab: Floor:NLRS_23_FL Kanaalplaat_d=260, Floor:NLRS_23_FL Kanaalplaat_d=260:1011174:2
In: 00 begane grond b.k. ruwe vloer
Type - PredefinedType: FLOOR; Material: IMd_beton_prefab_kanaalplaat 260 mm
Type - Pset_ElementShading - Roughness: 304.8 mm
Type - Pset_ProductRequirements - Category: Floors
Type - Pset_QuantityTakeOff - Reference: Floor:NLRS_23_FL Kanaalplaat_d=260
Type - Pset_ReinforcementBarPitchOfSlab - Description: KP260; Reference: Floor:NLRS_23_FL Kanaalplaat_d=260
Type - Pset_SlabCommon - IsExternal: no; Reference: Floor:NLRS_23_FL Kanaalplaat_d=260
Type - S_IMd_IFC_(--)_FL_Vloeren - Assembly Code: 23.21; Assembly Description: vloeren; constructief, vrijdragende vloeren; Structural Material: IMd_beton_prefab_kanaalplaat; Keynote: 23,42
Classification: 23.21 vloeren; constructief, vrijdragende vloeren (NL-SfB nummercode)
Pset_SlabCommon - LoadBearing: yes; PitchAngle: 0 deg
S_IMd_IFC_(--)_FL_Vloeren - Family: Floor: NLRS_23_FL Kanaalplaat_d=260; Type: Floor: NLRS_23_FL Kanaalplaat_d=260; Level: Level: 00 begane grond b.k. ruwe vloer; Height Offset From Level: -560 mm; Elevation at Top: -630 mm; Elevation at Bottom: -890 mm; Area: 56.7945 m2; Volume: 14.7673 m3; Perimeter: 64070.4 mm
BaseQuantities - GrossArea: 26.4985 m2; NetArea: 130.247 m2; NetVolume: 14.7673 m3; Perimeter: 64070.4 mm

# IfcSlab: Floor:NLRS_23_FL Kanaalplaat_d=260, Floor:NLRS_23_FL Kanaalplaat_d=260:1011174
In: 00 begane grond b.k. ruwe vloer
Type - PredefinedType: FLOOR
Type - Pset_ElementShading - Roughness: 304.8 mm
Type - Pset_ProductRequirements - Category: Floors
Type - Pset_QuantityTakeOff - Reference: Floor:NLRS_23_FL Kanaalplaat_d=260
Type - Pset_ReinforcementBarPitchOfSlab - Description: KP260; Reference: Floor:NLRS_23_FL Kanaalplaat_d=260
Type - Pset_SlabCommon - IsExternal: no; Reference: Floor:NLRS_23_FL Kanaalplaat_d=260
Type - S_IMd_IFC_(--)_FL_Vloeren - Assembly Code: 23.21; Assembly Description: vloeren; constructief, vrijdragende vloeren; Structural Material: IMd_beton_prefab_kanaalplaat; Keynote: 23,42
Classification: 23.21 vloeren; constructief, vrijdragende vloeren (NL-SfB nummercode); Material: IMd_beton_prefab_kanaalplaat 260 mm
Pset_SlabCommon - LoadBearing: yes; PitchAngle: 0 deg
S_IMd_IFC_(--)_FL_Vloeren - Family: Floor: NLRS_23_FL Kanaalplaat_d=260; Type: Floor: NLRS_23_FL Kanaalplaat_d=260; Level: Level: 00 begane grond b.k. ruwe vloer; Height Offset From Level: -560 mm; Elevation at Top: -630 mm; Elevation at Bottom: -890 mm; Area: 56.7945 m2; Volume: 14.7673 m3; Perimeter: 64070.4 mm
BaseQuantities - GrossArea: 30.3002 m2; NetArea: 130.247 m2; NetVolume: 14.7673 m3; Perimeter: 64070.4 mm

# IfcSlab: Floor:NLRS_23_FL Kanaalplaat_d=260_druklaag_d=70_geisoleerd_rc4, Floor:NLRS_23_FL Kanaalplaat_d=260_druklaag_d=70_geisoleerd_rc4:1000980
In: 00 begane grond b.k. ruwe vloer
Type - PredefinedType: FLOOR; Material: IMd_beton_druklaag 70 mm, IMd_beton_prefab_kanaalplaat 260 mm, IMd_isolatie 140 mm
Type - Pset_ElementShading - Roughness: 304.8 mm
Type - Pset_ProductRequirements - Category: Floors
Type - Pset_QuantityTakeOff - Reference: Floor:NLRS_23_FL Kanaalplaat_d=260_druklaag_d=70_geisoleerd_rc4
Type - Pset_ReinforcementBarPitchOfSlab - Description: GKP260+DL70; Reference: Floor:NLRS_23_FL Kanaalplaat_d=260_druklaag_d=70_geisoleerd_rc4
Type - Pset_SlabCommon - IsExternal: no; Reference: Floor:NLRS_23_FL Kanaalplaat_d=260_druklaag_d=70_geisoleerd_rc4
Type - S_IMd_IFC_(--)_FL_Vloeren - Assembly Code: 23.21; Assembly Description: vloeren; constructief, vrijdragende vloeren; Structural Material: IMd_beton_prefab_kanaalplaat; Keynote: 23,42
Classification: 23.21 vloeren; constructief, vrijdragende vloeren (NL-SfB nummercode)
Pset_SlabCommon - LoadBearing: yes; PitchAngle: 0 deg; IsExternal: yes
S_IMd_IFC_(--)_FL_Vloeren - Height Offset From Level: 0 mm; Family: Floor: NLRS_23_FL Kanaalplaat_d=260_druklaag_d=70_geisoleerd_rc4; Type: Floor: NLRS_23_FL Kanaalplaat_d=260_druklaag_d=70_geisoleerd_rc4; Level: Level: 00 begane grond b.k. ruwe vloer; Elevation at Top: -70 mm; Elevation at Bottom: -540 mm; Area: 121.973 m2; Volume: 57.3275 m3; Perimeter: 48516.6 mm
BaseQuantities - GrossArea: 121.973 m2; NetArea: 266.75 m2; GrossVolume: 57327.5 m3; NetVolume: 57.3275 m3; Perimeter: 48516.6 mm; Width: 470 mm

# IfcSlab: Floor:NLRS_23_FL stalen liggers_bk_h=160, Floor:NLRS_23_FL stalen liggers_bk_h=160:982200:2
In: 02 2e verd. b.k. ruwe vloer
Type - PredefinedType: FLOOR; Material: IMd_staal 160 mm
Type - Pset_ElementShading - Roughness: 304.8 mm
Type - Pset_ProductRequirements - Category: Floors
Type - Pset_QuantityTakeOff - Reference: Floor:NLRS_23_FL stalen liggers_bk_h=160
Type - Pset_ReinforcementBarPitchOfSlab - Description: Bouwkundige stalen liggers; Reference: Floor:NLRS_23_FL stalen liggers_bk_h=160
Type - Pset_SlabCommon - IsExternal: no; Reference: Floor:NLRS_23_FL stalen liggers_bk_h=160
Type - S_IMd_IFC_(--)_FL_Vloeren - Assembly Code: 23.21; Assembly Description: vloeren; constructief, vrijdragende vloeren; Structural Material: IMd_staal; Keynote: 23,42
Classification: 23.21 vloeren; constructief, vrijdragende vloeren (NL-SfB nummercode)
Pset_SlabCommon - LoadBearing: yes; PitchAngle: 4.18085 deg
S_IMd_IFC_(--)_FL_Vloeren - Height Offset From Level: 0 mm; Family: Floor: NLRS_23_FL stalen liggers_bk_h=160; Type: Floor: NLRS_23_FL stalen liggers_bk_h=160; Level: Level: 03 derde verdieping; Area: 157.773 m2; Volume: 25.2453 m3; Perimeter: 103248 mm
BaseQuantities - GrossArea: 53.0876 m2; NetArea: 332.109 m2; NetVolume: 25.2453 m3; Perimeter: 103248 mm

# IfcSlab: Floor:NLRS_23_FL stalen liggers_bk_h=160, Floor:NLRS_23_FL stalen liggers_bk_h=160:982200
In: 02 2e verd. b.k. ruwe vloer
Type - PredefinedType: FLOOR
Type - Pset_ElementShading - Roughness: 304.8 mm
Type - Pset_ProductRequirements - Category: Floors
Type - Pset_QuantityTakeOff - Reference: Floor:NLRS_23_FL stalen liggers_bk_h=160
Type - Pset_ReinforcementBarPitchOfSlab - Description: Bouwkundige stalen liggers; Reference: Floor:NLRS_23_FL stalen liggers_bk_h=160
Type - Pset_SlabCommon - IsExternal: no; Reference: Floor:NLRS_23_FL stalen liggers_bk_h=160
Type - S_IMd_IFC_(--)_FL_Vloeren - Assembly Code: 23.21; Assembly Description: vloeren; constructief, vrijdragende vloeren; Structural Material: IMd_staal; Keynote: 23,42
Classification: 23.21 vloeren; constructief, vrijdragende vloeren (NL-SfB nummercode); Material: IMd_staal 160 mm
Pset_SlabCommon - LoadBearing: yes; PitchAngle: 4.18085 deg
S_IMd_IFC_(--)_FL_Vloeren - Height Offset From Level: 0 mm; Family: Floor: NLRS_23_FL stalen liggers_bk_h=160; Type: Floor: NLRS_23_FL stalen liggers_bk_h=160; Level: Level: 03 derde verdieping; Area: 157.773 m2; Volume: 25.2453 m3; Perimeter: 103248 mm
BaseQuantities - GrossArea: 104.275 m2; NetArea: 332.109 m2; NetVolume: 25.2453 m3; Perimeter: 103248 mm

# IfcWall: Basic Wall:NLRS_28_WA HSB_d=271 (2)
In: 00 begane grond b.k. ruwe vloer
Type - PredefinedType: STANDARD; Material: IMd_underlayment 18 mm, IMd_hout 270 mm, IMd_underlayment 18 mm
Type - Pset_ElementShading - Roughness: 304.8 mm
Type - Pset_ProductRequirements - Category: Walls
Type - Pset_QuantityTakeOff - Reference: Basic Wall:NLRS_28_WA HSB_d=271
Type - Pset_ReinforcementBarPitchOfWall - Description: Wand d=270; Reference: Basic Wall:NLRS_28_WA HSB_d=271
Type - Pset_WallCommon - IsExternal: no; Reference: Basic Wall:NLRS_28_WA HSB_d=271
Type - S_IMd_IFC_(--)_WA_Wanden - Assembly Code: 28.20; Assembly Description: hoofddraagconstructies; wanden en vloeren, algemeen (verzamelniveau); Description: Wand d=270; Type Comments: d=270; Structural Material: IMd_hout; Width: 306 mm
Classification: 28.20 hoofddraagconstructies; wanden en vloeren, algemeen (verzamelniveau) (NL-SfB nummercode)
Pset_WallCommon - LoadBearing: yes; ExtendToStructure: no
S_IMd_IFC_(--)_WA_Wanden - Base Offset: 0 mm; Family: Basic Wall: NLRS_28_WA HSB_d=271; Type: Basic Wall: NLRS_28_WA HSB_d=271; Base Constraint: Level: 00 begane grond b.k. ruwe vloer; Top Constraint: Level: 02 2e verd. b.k. ruwe vloer
Name (Basic Wall:NLRS_28_WA HSB_d=271:...) | Top Offset (mm) | Unconnected Height (mm) | Length (mm) | Area (m2) | Volume (m3)
985206 | -200 | 3570 | 6565.12 | 20.3775 | 6.1747
986229 | 1350 | 5120 | 7719.05 | 34.4853 | 10.4837

# IfcWallStandardCase: Basic Wall:NLRS_16_WA Funderingsbalk_beton_ihwg_500x600 (11)
In: -01 kelder
Type - PredefinedType: STANDARD; Material: IMd_beton_IHWG 500 mm
Type - Pset_ElementShading - Roughness: 304.8 mm
Type - Pset_ProductRequirements - Category: Walls
Type - Pset_QuantityTakeOff - Reference: Basic Wall:NLRS_16_WA Funderingsbalk_beton_ihwg_500x600
Type - Pset_ReinforcementBarPitchOfWall - Description: Balk 500x600; Reference: Basic Wall:NLRS_16_WA Funderingsbalk_beton_ihwg_500x600
Type - Pset_WallCommon - Reference: Basic Wall:NLRS_16_WA Funderingsbalk_beton_ihwg_500x600; IsExternal: yes
Type - S_IMd_IFC_(--)_WA_Wanden - Assembly Code: 16.10; Assembly Description: funderingsconstructies; voeten en balken, algemeen (verzamelniveau); Description: Balk 500x600; Structural Material: IMd_beton_IHWG; Width: 500 mm; IfcExportAs: IFcBeam
Classification: 16.10 funderingsconstructies; voeten en balken, algemeen (verzamelniveau) (NL-SfB nummercode)
BaseQuantities - Height: 600 mm; Width: 500 mm
Pset_WallCommon - LoadBearing: yes; ExtendToStructure: no
S_IMd_IFC_(--)_WA_Wanden - Family: Basic Wall: NLRS_16_WA Funderingsbalk_beton_ihwg_500x600; Type: Basic Wall: NLRS_16_WA Funderingsbalk_beton_ihwg_500x600; Base Constraint: Level: 00 o.k. fundering; Base Offset: -140 mm; Top Constraint: Level: 00 b.k. fundering; Top Offset: -140 mm; Unconnected Height: 600 mm; Comments: Betonwand D= mm
Name (Basic Wall:NLRS_16_WA Funderingsbalk_beton_ihwg_500x600:...) | BaseQuantities, Length (mm) | GrossFootprintArea (m2) | S_IMd_IFC_(--)_WA_Wanden, Length (mm) | Area (m2) | Volume (m3) | GrossVolume (m3) | GrossSideArea (m2) = NetSideArea (m2) | NetVolume (m3)
999331 | 16275.3 | 8.12985 | 16267.5 | 9.76521 | 4.87791
999534 | 17864.5 | 8.93225 | 17864.5 | 10.7187 | 5.35935 | 5359.35 | 10.7187 | 5.35935
999615 | 6387.15 | 3.14808 | 6562.2 | 3.83229 | 1.88885 | 1916.15 | 3.83229 | 1.88885
999687 | 3321.36 | 1.65746 | 3314.02 | 2.26123 | 0.994497
999701 | 1836.43 | 0.909825 | 2074.45 | 1.27774 | 0.547232
999715 | 2444.75 | 1.16345 | 2602.26 | 1.60192 | 0.698055
1000308 | 20333.1 | 10.0852 | 20164.4 | 12.1138 | 6.05111 | 6056.91 | 12.1138 | 6.05111
1000475 | 6700 | 3.35 | 7200 | 4.02 | 2.01 | 2010 | 4.02 | 2.01
1000701 | 9284.67 | 4.64233 | 9784.67 | 5.2708 | 2.6354 | 2635.4 | 5.2708 | 2.6354
1000862 | 4060.31 | 1.99431 | 4248.7 | 2.43619 | 1.19659 | 1218.09 | 2.43619 | 1.19659
1015409 | 690.154 | 0.257548 | 353.318 | 0.338361 | 0.154529

# IfcWallStandardCase: Basic Wall:NLRS_16_WA Funderingsbalk_beton_prefab_150x810 (6)
In: 00 begane grond b.k. ruwe vloer
Type - PredefinedType: STANDARD; Material: IMd_beton_prefab 150 mm
Type - Pset_ElementShading - Roughness: 304.8 mm
Type - Pset_ProductRequirements - Category: Walls
Type - Pset_QuantityTakeOff - Reference: Basic Wall:NLRS_16_WA Funderingsbalk_beton_prefab_150x810
Type - Pset_ReinforcementBarPitchOfWall - Description: Prefab balk 150x810; Reference: Basic Wall:NLRS_16_WA Funderingsbalk_beton_prefab_150x810
Type - Pset_WallCommon - IsExternal: yes; Reference: Basic Wall:NLRS_16_WA Funderingsbalk_beton_prefab_150x810
Type - S_IMd_IFC_(--)_WA_Wanden - Assembly Code: 16.10; Assembly Description: funderingsconstructies; voeten en balken, algemeen (verzamelniveau); Description: Prefab balk 150x810; Structural Material: IMd_beton_prefab; Width: 150 mm; IfcExportAs: IFcBeam
Classification: 16.10 funderingsconstructies; voeten en balken, algemeen (verzamelniveau) (NL-SfB nummercode)
BaseQuantities - Height: 810 mm; Width: 150 mm
Pset_WallCommon - LoadBearing: yes; ExtendToStructure: no
S_IMd_IFC_(--)_WA_Wanden - Family: Basic Wall: NLRS_16_WA Funderingsbalk_beton_prefab_150x810; Type: Basic Wall: NLRS_16_WA Funderingsbalk_beton_prefab_150x810; Base Constraint: Level: 00 begane grond; Base Offset: -890 mm; Top Constraint: Level: 00 begane grond; Top Offset: -80 mm; Unconnected Height: 810 mm; Comments: Betonwand D= mm
Name (Basic Wall:NLRS_16_WA Funderingsbalk_beton_prefab_150x810:...) | BaseQuantities, Length (mm) | GrossFootprintArea (m2) | S_IMd_IFC_(--)_WA_Wanden, Length (mm) | Area (m2) | Volume (m3) | GrossVolume (m3) | GrossSideArea (m2) = NetSideArea (m2) | NetVolume (m3)
1064814 | 5953.99 | 0.886157 | 5952.2 | 5.20148 | 0.723212
1066405 | 1799.95 | 0.269992 | 1799.95 | 1.45796 | 0.218694 | 218.694 | 1.45796 | 0.218694
1066582 | 1799.95 | 0.269992 | 1799.95 | 1.45796 | 0.218694 | 218.694 | 1.45796 | 0.218694
1066785 | 1850 | 0.2775 | 2000 | 1.4985 | 0.224775 | 224.775 | 1.4985 | 0.224775
1066863 | 2150 | 0.3225 | 2000 | 1.7415 | 0.261225 | 261.225 | 1.7415 | 0.261225
1067359 | 50.0968 | 0.00723013 | 48.2382 | 0.0405784 | 0.00585641 | 18.2265 | 0.12151 | 0.00585641

# IfcWallStandardCase: Basic Wall:NLRS_16_WA Funderingsbalk_beton_prefab_300x800 (11)
In: 00 begane grond b.k. ruwe vloer
Type - PredefinedType: STANDARD; Material: IMd_beton_prefab 300 mm
Type - Pset_ElementShading - Roughness: 304.8 mm
Type - Pset_ProductRequirements - Category: Walls
Type - Pset_QuantityTakeOff - Reference: Basic Wall:NLRS_16_WA Funderingsbalk_beton_prefab_300x800
Type - Pset_ReinforcementBarPitchOfWall - Description: Prefab balk 300x800; Reference: Basic Wall:NLRS_16_WA Funderingsbalk_beton_prefab_300x800
Type - Pset_WallCommon - IsExternal: yes; Reference: Basic Wall:NLRS_16_WA Funderingsbalk_beton_prefab_300x800
Type - S_IMd_IFC_(--)_WA_Wanden - Assembly Code: 16.10; Assembly Description: funderingsconstructies; voeten en balken, algemeen (verzamelniveau); Description: Prefab balk 300x800; Structural Material: IMd_beton_prefab; Width: 300 mm; IfcExportAs: IFcBeam
Classification: 16.10 funderingsconstructies; voeten en balken, algemeen (verzamelniveau) (NL-SfB nummercode)
BaseQuantities - Height: 800 mm; Width: 300 mm
Pset_WallCommon - LoadBearing: yes; ExtendToStructure: no
S_IMd_IFC_(--)_WA_Wanden - Family: Basic Wall: NLRS_16_WA Funderingsbalk_beton_prefab_300x800; Type: Basic Wall: NLRS_16_WA Funderingsbalk_beton_prefab_300x800; Base Constraint: Level: 00 begane grond; Base Offset: -890 mm; Top Constraint: Level: 00 begane grond; Top Offset: -90 mm; Unconnected Height: 800 mm; Comments: Betonwand D= mm
Name (Basic Wall:NLRS_16_WA Funderingsbalk_beton_prefab_300x800:...) | BaseQuantities, Length (mm) | GrossFootprintArea (m2) | GrossVolume (m3) | GrossSideArea (m2) = NetSideArea (m2) | NetVolume (m3) | S_IMd_IFC_(--)_WA_Wanden, Length (mm) | Area (m2) | Volume (m3)
1002572 | 7090.62 | 2.12718 | 1701.75 | 5.67249 | 1.70174 | 7090.58 | 5.67249 | 1.70174
1002653 | 14283.6 | 4.28507 | 3428.06 | 11.4269 | 3.42806 | 14133.6 | 11.4269 | 3.42806
1002726 | 11173.8 | 3.3442 | 2681.71 | 8.93903 | 2.67536 | 11449.7 | 8.93903 | 2.67536
1002806 | 12191 | 3.63882 |  |  |  | 12491 | 9.75283 | 2.91105
1003161 | 774.301 | 0.225265 |  |  |  | 903.21 | 0.616283 | 0.180212
1003673 | 300 | 0.09 | 72 | 0.24 | 0.072 | 300 | 0.24 | 0.072
1010549 | 300 | 0.09 | 72 | 0.24 | 0.072 | 300 | 0.24 | 0.072
1010604 | 300 | 0.09 | 72 | 0.24 | 0.072 | 300 | 0.24 | 0.072
1015176 | 365.805 | 0.0924446 |  |  |  | 195 | 0.245962 | 0.0739558
1015811 | 357.526 | 0.0913884 | 73.1107 | 0.243702 | 0.0731107 | 226.225 | 0.243702 | 0.0731107
1069444 | 6444.32 | 1.92537 | 1546.64 | 5.15546 | 1.5403 | 6570.22 | 5.15546 | 1.5403

# IfcWallStandardCase: Basic Wall:NLRS_16_WA Funderingsnok_beton_ihwg_250x150 (6)
In: -01 kelder
Type - PredefinedType: STANDARD; Material: IMd_beton_IHWG 150 mm
Type - Pset_ElementShading - Roughness: 304.8 mm
Type - Pset_ProductRequirements - Category: Walls
Type - Pset_QuantityTakeOff - Reference: Basic Wall:NLRS_16_WA Funderingsnok_beton_ihwg_250x150
Type - Pset_ReinforcementBarPitchOfWall - Description: Nok 250x150; Reference: Basic Wall:NLRS_16_WA Funderingsnok_beton_ihwg_250x150
Type - Pset_WallCommon - IsExternal: yes; Reference: Basic Wall:NLRS_16_WA Funderingsnok_beton_ihwg_250x150
Type - S_IMd_IFC_(--)_WA_Wanden - Assembly Code: 16.10; Assembly Description: funderingsconstructies; voeten en balken, algemeen (verzamelniveau); Description: Nok 250x150; Structural Material: IMd_beton_IHWG; Width: 150 mm; IfcExportAs: IFcBeam
Classification: 16.10 funderingsconstructies; voeten en balken, algemeen (verzamelniveau) (NL-SfB nummercode)
BaseQuantities - Height: 250 mm; Width: 150 mm
Pset_WallCommon - LoadBearing: yes; ExtendToStructure: no
S_IMd_IFC_(--)_WA_Wanden - Family: Basic Wall: NLRS_16_WA Funderingsnok_beton_ihwg_250x150; Type: Basic Wall: NLRS_16_WA Funderingsnok_beton_ihwg_250x150; Base Constraint: Level: 00 o.k. fundering; Base Offset: -140 mm; Top Constraint: Level: 00 o.k. fundering; Top Offset: 110 mm; Unconnected Height: 250 mm; Comments: Betonwand D= mm
Name (Basic Wall:NLRS_16_WA Funderingsnok_beton_ihwg_250x150:...) | BaseQuantities, Length (mm) | GrossFootprintArea (m2) | GrossVolume (m3) | GrossSideArea (m2) = NetSideArea (m2) | NetVolume (m3) | S_IMd_IFC_(--)_WA_Wanden, Length (mm) | Area (m2) | Volume (m3)
1012436 | 16190 | 2.4285 | 607.125 | 4.0475 | 0.607125 | 16440 | 4.0475 | 0.607125
1012650 | 1934.67 | 0.2902 | 72.5501 | 0.483667 | 0.0725501 | 2259.67 | 0.483667 | 0.0725501
1012863 | 9812.83 | 1.4687 | 367.981 | 2.45321 | 0.367174 | 9713.3 | 2.45321 | 0.367174
1012918 | 3760.89 | 0.560908 | 141.034 | 0.940223 | 0.140227 | 3817.41 | 0.940223 | 0.140227
1013276 | 2453.46 | 0.362251 |  |  |  | 2160.71 | 0.632614 | 0.0911099
1034314 | 2702.26 | 0.405339 | 101.335 | 0.675566 | 0.101335 | 2777.26 | 0.675566 | 0.101335

# IfcWallStandardCase: Basic Wall:NLRS_16_WA Funderingspoer_beton_ihwg_400x400x1530, Basic Wall:NLRS_16_WA Funderingspoer_beton_ihwg_400x400x1530:1046845
In: 00 begane grond b.k. ruwe vloer
Type - PredefinedType: STANDARD; Material: IMd_beton_IHWG 400 mm
Type - Pset_ElementShading - Roughness: 304.8 mm
Type - Pset_ProductRequirements - Category: Walls
Type - Pset_QuantityTakeOff - Reference: Basic Wall:NLRS_16_WA Funderingspoer_beton_ihwg_400x400x1530
Type - Pset_ReinforcementBarPitchOfWall - Description: Opstort 400x400x1530; Reference: Basic Wall:NLRS_16_WA Funderingspoer_beton_ihwg_400x400x1530
Type - Pset_WallCommon - IsExternal: yes; Reference: Basic Wall:NLRS_16_WA Funderingspoer_beton_ihwg_400x400x1530
Type - S_IMd_IFC_(--)_WA_Wanden - Assembly Code: 16.10; Assembly Description: funderingsconstructies; voeten en balken, algemeen (verzamelniveau); Description: Opstort 400x400x1530; Structural Material: IMd_beton_IHWG; Width: 400 mm; IfcExportAs: IFcBeam
Classification: 16.10 funderingsconstructies; voeten en balken, algemeen (verzamelniveau) (NL-SfB nummercode)
BaseQuantities - Height: 1530 mm; Length: 400 mm; Width: 400 mm; GrossFootprintArea: 0.16 m2; GrossVolume: 244.8 m3; GrossSideArea: 0.612 m2; NetSideArea: 0.612 m2; NetVolume: 0.2448 m3
Pset_WallCommon - LoadBearing: yes; ExtendToStructure: no
S_IMd_IFC_(--)_WA_Wanden - Family: Basic Wall: NLRS_16_WA Funderingspoer_beton_ihwg_400x400x1530; Type: Basic Wall: NLRS_16_WA Funderingspoer_beton_ihwg_400x400x1530; Base Constraint: Level: 00 begane grond b.k. ruwe vloer; Base Offset: -820 mm; Top Constraint: Level: 00 begane grond; Top Offset: 639.999 mm; Unconnected Height: 1530 mm; Length: 400 mm; Area: 0.612 m2; Volume: 0.2448 m3; Comments: Betonwand D= mm

# IfcWallStandardCase: Basic Wall:NLRS_28_WA HSB_d=271 (13)
In: 00 begane grond b.k. ruwe vloer
Type - PredefinedType: STANDARD; Material: IMd_underlayment 18 mm, IMd_hout 270 mm, IMd_underlayment 18 mm
Type - Pset_ElementShading - Roughness: 304.8 mm
Type - Pset_ProductRequirements - Category: Walls
Type - Pset_QuantityTakeOff - Reference: Basic Wall:NLRS_28_WA HSB_d=271
Type - Pset_ReinforcementBarPitchOfWall - Description: Wand d=270; Reference: Basic Wall:NLRS_28_WA HSB_d=271
Type - Pset_WallCommon - IsExternal: no; Reference: Basic Wall:NLRS_28_WA HSB_d=271
Type - S_IMd_IFC_(--)_WA_Wanden - Assembly Code: 28.20; Assembly Description: hoofddraagconstructies; wanden en vloeren, algemeen (verzamelniveau); Description: Wand d=270; Type Comments: d=270; Structural Material: IMd_hout; Width: 306 mm
Classification: 28.20 hoofddraagconstructies; wanden en vloeren, algemeen (verzamelniveau) (NL-SfB nummercode)
BaseQuantities - Width: 306 mm
Pset_WallCommon - LoadBearing: yes
S_IMd_IFC_(--)_WA_Wanden - Family: Basic Wall: NLRS_28_WA HSB_d=271; Type: Basic Wall: NLRS_28_WA HSB_d=271
Name (Basic Wall:NLRS_28_WA HSB_d=271:...) | Height (mm) | BaseQuantities, Length (mm) | GrossFootprintArea (m2) | GrossVolume (m3) | GrossSideArea (m2) | NetSideArea (m2) | NetVolume (m3) | ExtendToStructure | Base Constraint | Base Offset (mm) | Top Constraint | Top Offset (mm) | Unconnected Height (mm) | S_IMd_IFC_(--)_WA_Wanden, Length (mm) | Area (m2) | Volume (m3)
983627 | 7346.56 | 9787.67 | 2.99503 | 18237.5 | 59.5997 | 59.5997 | 18.231 | yes | Level: 00 begane grond | 0 | Level: 03 3e verd. o.k. ruwe vloer | 5000 | 10680 | 9787.67 | 59.5997 | 18.231
984148 | 5050 | 1201.77 | 0.354309 | 1857.09 | 6.06892 | 6.06892 | 1.78926 | no | Level: 00 begane grond | 0 | Level: 03 3e verd. o.k. ruwe vloer | 5000 | 10680 | 1151.7 | 6.06892 | 1.78926
984564 | 6871.71 | 18646 | 5.22402 | 29643.9 | 96.8753 | 90.5609 | 27.708 | yes | Level: 00 begane grond | -10 | Level: 03 3e verd. o.k. ruwe vloer | 5000 | 10690 | 18274.5 | 90.5609 | 27.708
984650 | 7126.41 | 6900 | 2.1114 | 14534.9 | 47.4995 | 47.4995 | 14.5283 | yes | Level: 00 begane grond b.k. ruwe vloer | 0 | Level: 03 3e verd. o.k. ruwe vloer | 5000 | 10750 | 7206 | 47.4995 | 14.5283
984819 | 7439.29 | 16053.8 | 4.53093 | 34960.3 | 114.249 | 93.6678 | 28.6131 | yes | Level: 00 begane grond b.k. ruwe vloer | 0 | Level: 03 3e verd. o.k. ruwe vloer | 5000 | 10750 | 16053.5 | 93.6678 | 28.6131
985810 | 3570 | 1921.02 | 0.587794 |  |  |  |  | no | Level: 00 begane grond b.k. ruwe vloer | 0 | Level: 02 2e verd. b.k. ruwe vloer | -200 | 3570 | 1920.84 | 7.52413 | 2.09883
986078 | 5120 | 3430.1 | 1.04936 |  |  |  |  | no | Level: 00 begane grond b.k. ruwe vloer | 0 | Level: 02 2e verd. b.k. ruwe vloer | 1350 | 5120 | 3429.93 | 19.0098 | 5.3722
986345 | 3510 | 3999.23 | 1.22376 | 4295.41 | 14.0373 | 14.0373 | 4.29541 | no | Level: 00 begane grond | -10 | Level: 02 2e verd. b.k. ruwe vloer | -200 | 3510 | 3999.23 | 14.0373 | 4.29541
986504 | 6284.7 | 7511.59 | 2.29855 | 12998.7 | 42.4796 | 42.4796 | 12.9961 | yes | Level: 00 begane grond | -10 | Level: 03 3e verd. o.k. ruwe vloer | 5000 | 10690 | 7205.58 | 42.4796 | 12.9961
987289 | 6292.36 | 12606 | 3.85744 | 16341.1 | 53.4022 | 53.4022 | 16.3121 | yes | Level: 00 begane grond | -10 | Level: 03 3e verd. o.k. ruwe vloer | 5000 | 10690 | 12606 | 53.4022 | 16.3121
987307 | 6166.13 | 6900.01 | 2.1114 | 12489.6 | 40.8157 | 39.6075 | 12.1174 | yes | Level: 00 begane grond | -10 | Level: 03 3e verd. o.k. ruwe vloer | 5000 | 10690 | 7206 | 39.6075 | 12.1174
987491 | 5758.52 | 14401.5 | 4.40685 | 22968.7 | 75.0612 | 75.0612 | 22.9315 | yes | Level: 00 begane grond | -10 | Level: 03 3e verd. o.k. ruwe vloer | 5000 | 10690 | 14248.5 | 75.0612 | 22.9315
987616 | 3510 | 3972.37 | 1.21562 |  |  |  |  | no | Level: 00 begane grond | -10 | Level: 02 2e verd. b.k. ruwe vloer | -200 | 3510 | 3972.37 | 14.7305 | 4.26663
